VERSION 5.7 ;
  NOWIREEXTENSIONATPIN ON ;
  DIVIDERCHAR "/" ;
  BUSBITCHARS "[]" ;
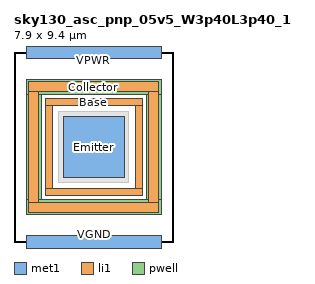
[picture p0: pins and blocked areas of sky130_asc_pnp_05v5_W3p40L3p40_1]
MACRO sky130_asc_pnp_05v5_W3p40L3p40_1
  CLASS CORE ;
  FOREIGN sky130_asc_pnp_05v5_W3p40L3p40_1 ;
  ORIGIN 0.000 0.000 ;
  SIZE 7.900 BY 9.400 ;
  SITE unitasc ;
  PIN Emitter
    DIRECTION INOUT ;
    ANTENNADIFFAREA 11.559999 ;
    PORT
      LAYER met1 ;
        RECT 2.425 3.175 5.475 6.225 ;
    END
  END Emitter
  PIN Base
    DIRECTION INOUT ;
    ANTENNAGATEAREA 26.728899 ;
    ANTENNADIFFAREA 6.408000 ;
    PORT
      LAYER li1 ;
        RECT 1.545 6.745 6.355 7.105 ;
        RECT 1.545 2.655 1.905 6.745 ;
        RECT 5.995 2.655 6.355 6.745 ;
        RECT 1.545 2.295 6.355 2.655 ;
    END
  END Base
  PIN Collector
    DIRECTION INOUT ;
    ANTENNADIFFAREA 11.988700 ;
    PORT
      LAYER pwell ;
        RECT 0.600 7.285 7.300 8.050 ;
        RECT 0.600 2.115 1.365 7.285 ;
        RECT 6.535 2.115 7.300 7.285 ;
        RECT 0.600 1.350 7.300 2.115 ;
      LAYER li1 ;
        RECT 0.730 7.425 7.170 7.920 ;
        RECT 0.730 1.975 1.225 7.425 ;
        RECT 6.675 1.975 7.170 7.425 ;
        RECT 0.730 1.480 7.170 1.975 ;
    END
  END Collector
  PIN VPWR
    DIRECTION INOUT ;
    USE POWER ;
    PORT
      LAYER met1 ;
        RECT 0.600 9.100 7.300 9.700 ;
    END
  END VPWR
  PIN VGND
    DIRECTION INOUT ;
    USE GROUND ;
    PORT
      LAYER met1 ;
        RECT 0.600 -0.300 7.300 0.300 ;
    END
  END VGND
  OBS
      LAYER li1 ;
        RECT 0.600 9.250 7.300 9.550 ;
        RECT 2.215 2.965 5.685 6.435 ;
        RECT 0.600 -0.150 7.300 0.150 ;
      LAYER mcon ;
        RECT 1.450 9.250 1.750 9.550 ;
        RECT 2.450 9.250 2.750 9.550 ;
        RECT 3.450 9.250 3.750 9.550 ;
        RECT 4.450 9.250 4.750 9.550 ;
        RECT 5.450 9.250 5.750 9.550 ;
        RECT 6.450 9.250 6.750 9.550 ;
        RECT 2.580 5.830 2.750 6.000 ;
        RECT 3.080 5.830 3.250 6.000 ;
        RECT 3.580 5.830 3.750 6.000 ;
        RECT 4.080 5.830 4.250 6.000 ;
        RECT 4.580 5.830 4.750 6.000 ;
        RECT 5.080 5.830 5.250 6.000 ;
        RECT 2.580 5.330 2.750 5.500 ;
        RECT 3.080 5.330 3.250 5.500 ;
        RECT 3.580 5.330 3.750 5.500 ;
        RECT 4.080 5.330 4.250 5.500 ;
        RECT 4.580 5.330 4.750 5.500 ;
        RECT 5.080 5.330 5.250 5.500 ;
        RECT 2.580 4.830 2.750 5.000 ;
        RECT 3.080 4.830 3.250 5.000 ;
        RECT 3.580 4.830 3.750 5.000 ;
        RECT 4.080 4.830 4.250 5.000 ;
        RECT 4.580 4.830 4.750 5.000 ;
        RECT 5.080 4.830 5.250 5.000 ;
        RECT 2.580 4.330 2.750 4.500 ;
        RECT 3.080 4.330 3.250 4.500 ;
        RECT 3.580 4.330 3.750 4.500 ;
        RECT 4.080 4.330 4.250 4.500 ;
        RECT 4.580 4.330 4.750 4.500 ;
        RECT 5.080 4.330 5.250 4.500 ;
        RECT 2.580 3.830 2.750 4.000 ;
        RECT 3.080 3.830 3.250 4.000 ;
        RECT 3.580 3.830 3.750 4.000 ;
        RECT 4.080 3.830 4.250 4.000 ;
        RECT 4.580 3.830 4.750 4.000 ;
        RECT 5.080 3.830 5.250 4.000 ;
        RECT 2.580 3.330 2.750 3.500 ;
        RECT 3.080 3.330 3.250 3.500 ;
        RECT 3.580 3.330 3.750 3.500 ;
        RECT 4.080 3.330 4.250 3.500 ;
        RECT 4.580 3.330 4.750 3.500 ;
        RECT 5.080 3.330 5.250 3.500 ;
        RECT 1.450 -0.150 1.750 0.150 ;
        RECT 2.450 -0.150 2.750 0.150 ;
        RECT 3.450 -0.150 3.750 0.150 ;
        RECT 4.450 -0.150 4.750 0.150 ;
        RECT 5.450 -0.150 5.750 0.150 ;
        RECT 6.450 -0.150 6.750 0.150 ;
  END
END sky130_asc_pnp_05v5_W3p40L3p40_1
END LIBRARY

